VERSION 5.7 ;
  NOWIREEXTENSIONATPIN ON ;
  DIVIDERCHAR "/" ;
  BUSBITCHARS "[]" ;
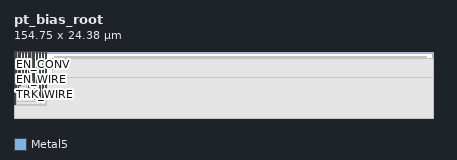
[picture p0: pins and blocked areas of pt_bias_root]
MACRO pt_bias_root
  CLASS BLOCK ;
  FOREIGN pt_bias_root ;
  ORIGIN -0.300 23.160 ;
  SIZE 154.750 BY 24.380 ;
  PIN VSS
    DIRECTION INOUT ;
    USE GROUND ;
    PORT
      LAYER Metal5 ;
        RECT 0.300 -18.320 0.740 1.220 ;
    END
  END VSS
  PIN ROOT_REF
    DIRECTION INPUT ;
    USE SIGNAL ;
    ANTENNAGATEAREA 192.000000 ;
    ANTENNADIFFAREA 2.080000 ;
    PORT
      LAYER Metal5 ;
        RECT 1.340 -12.920 1.780 1.220 ;
    END
  END ROOT_REF
  PIN EN_RF
    DIRECTION INPUT ;
    USE SIGNAL ;
    ANTENNAGATEAREA 2.000000 ;
    PORT
      LAYER Metal5 ;
        RECT 2.380 -11.120 2.820 1.220 ;
    END
  END EN_RF
  PIN EN_CONV
    DIRECTION INPUT ;
    USE SIGNAL ;
    ANTENNAGATEAREA 2.000000 ;
    PORT
      LAYER Metal5 ;
        RECT 3.420 -8.420 3.860 1.220 ;
    END
  END EN_CONV
  PIN EN_PLL
    DIRECTION INPUT ;
    USE SIGNAL ;
    ANTENNAGATEAREA 2.000000 ;
    PORT
      LAYER Metal5 ;
        RECT 4.460 -10.220 4.900 1.220 ;
    END
  END EN_PLL
  PIN EN_WIRE
    DIRECTION INPUT ;
    USE SIGNAL ;
    ANTENNAGATEAREA 2.000000 ;
    PORT
      LAYER Metal5 ;
        RECT 5.500 -12.020 5.940 1.220 ;
    END
  END EN_WIRE
  PIN EN_DEBUG
    DIRECTION INPUT ;
    USE SIGNAL ;
    ANTENNAGATEAREA 2.000000 ;
    PORT
      LAYER Metal5 ;
        RECT 6.540 -9.320 6.980 1.220 ;
    END
  END EN_DEBUG
  PIN TRK_RF
    DIRECTION OUTPUT ;
    USE SIGNAL ;
    ANTENNADIFFAREA 1.760000 ;
    PORT
      LAYER Metal5 ;
        RECT 7.580 -16.520 8.020 1.220 ;
    END
  END TRK_RF
  PIN TRK_CONV
    DIRECTION OUTPUT ;
    USE SIGNAL ;
    ANTENNADIFFAREA 1.760000 ;
    PORT
      LAYER Metal5 ;
        RECT 8.620 -13.820 9.060 1.220 ;
    END
  END TRK_CONV
  PIN TRK_PLL
    DIRECTION OUTPUT ;
    USE SIGNAL ;
    ANTENNADIFFAREA 1.760000 ;
    PORT
      LAYER Metal5 ;
        RECT 9.660 -15.620 10.100 1.220 ;
    END
  END TRK_PLL
  PIN TRK_WIRE
    DIRECTION OUTPUT ;
    USE SIGNAL ;
    ANTENNADIFFAREA 1.760000 ;
    PORT
      LAYER Metal5 ;
        RECT 10.700 -17.420 11.140 1.220 ;
    END
  END TRK_WIRE
  PIN TRK_DEBUG
    DIRECTION OUTPUT ;
    USE SIGNAL ;
    ANTENNADIFFAREA 1.760000 ;
    PORT
      LAYER Metal5 ;
        RECT 11.740 -14.720 12.180 1.220 ;
    END
  END TRK_DEBUG
  OBS
      LAYER Nwell ;
        RECT 15.330 -7.160 152.450 -0.600 ;
      LAYER Metal1 ;
        RECT 15.515 -7.060 152.350 -0.785 ;
      LAYER Metal2 ;
        RECT 14.430 -7.060 155.050 -1.360 ;
      LAYER Metal3 ;
        RECT 14.430 -23.160 155.050 -1.360 ;
      LAYER Metal4 ;
        RECT 0.320 -23.160 155.050 -8.360 ;
      LAYER Metal5 ;
        RECT 3.420 -10.820 3.860 -9.020 ;
        RECT 3.420 -11.720 4.900 -10.820 ;
        RECT 2.380 -12.620 4.900 -11.720 ;
        RECT 6.540 -12.620 6.980 -9.920 ;
        RECT 2.380 -13.520 6.980 -12.620 ;
        RECT 1.340 -17.120 6.980 -13.520 ;
        RECT 8.620 -16.220 9.060 -14.420 ;
        RECT 8.620 -17.120 10.100 -16.220 ;
        RECT 1.340 -18.020 10.100 -17.120 ;
        RECT 11.740 -18.020 12.180 -15.320 ;
        RECT 0.300 -18.600 0.380 -18.320 ;
        RECT 0.300 -18.680 0.740 -18.600 ;
        RECT 1.340 -18.680 12.180 -18.020 ;
  END
END pt_bias_root
END LIBRARY

